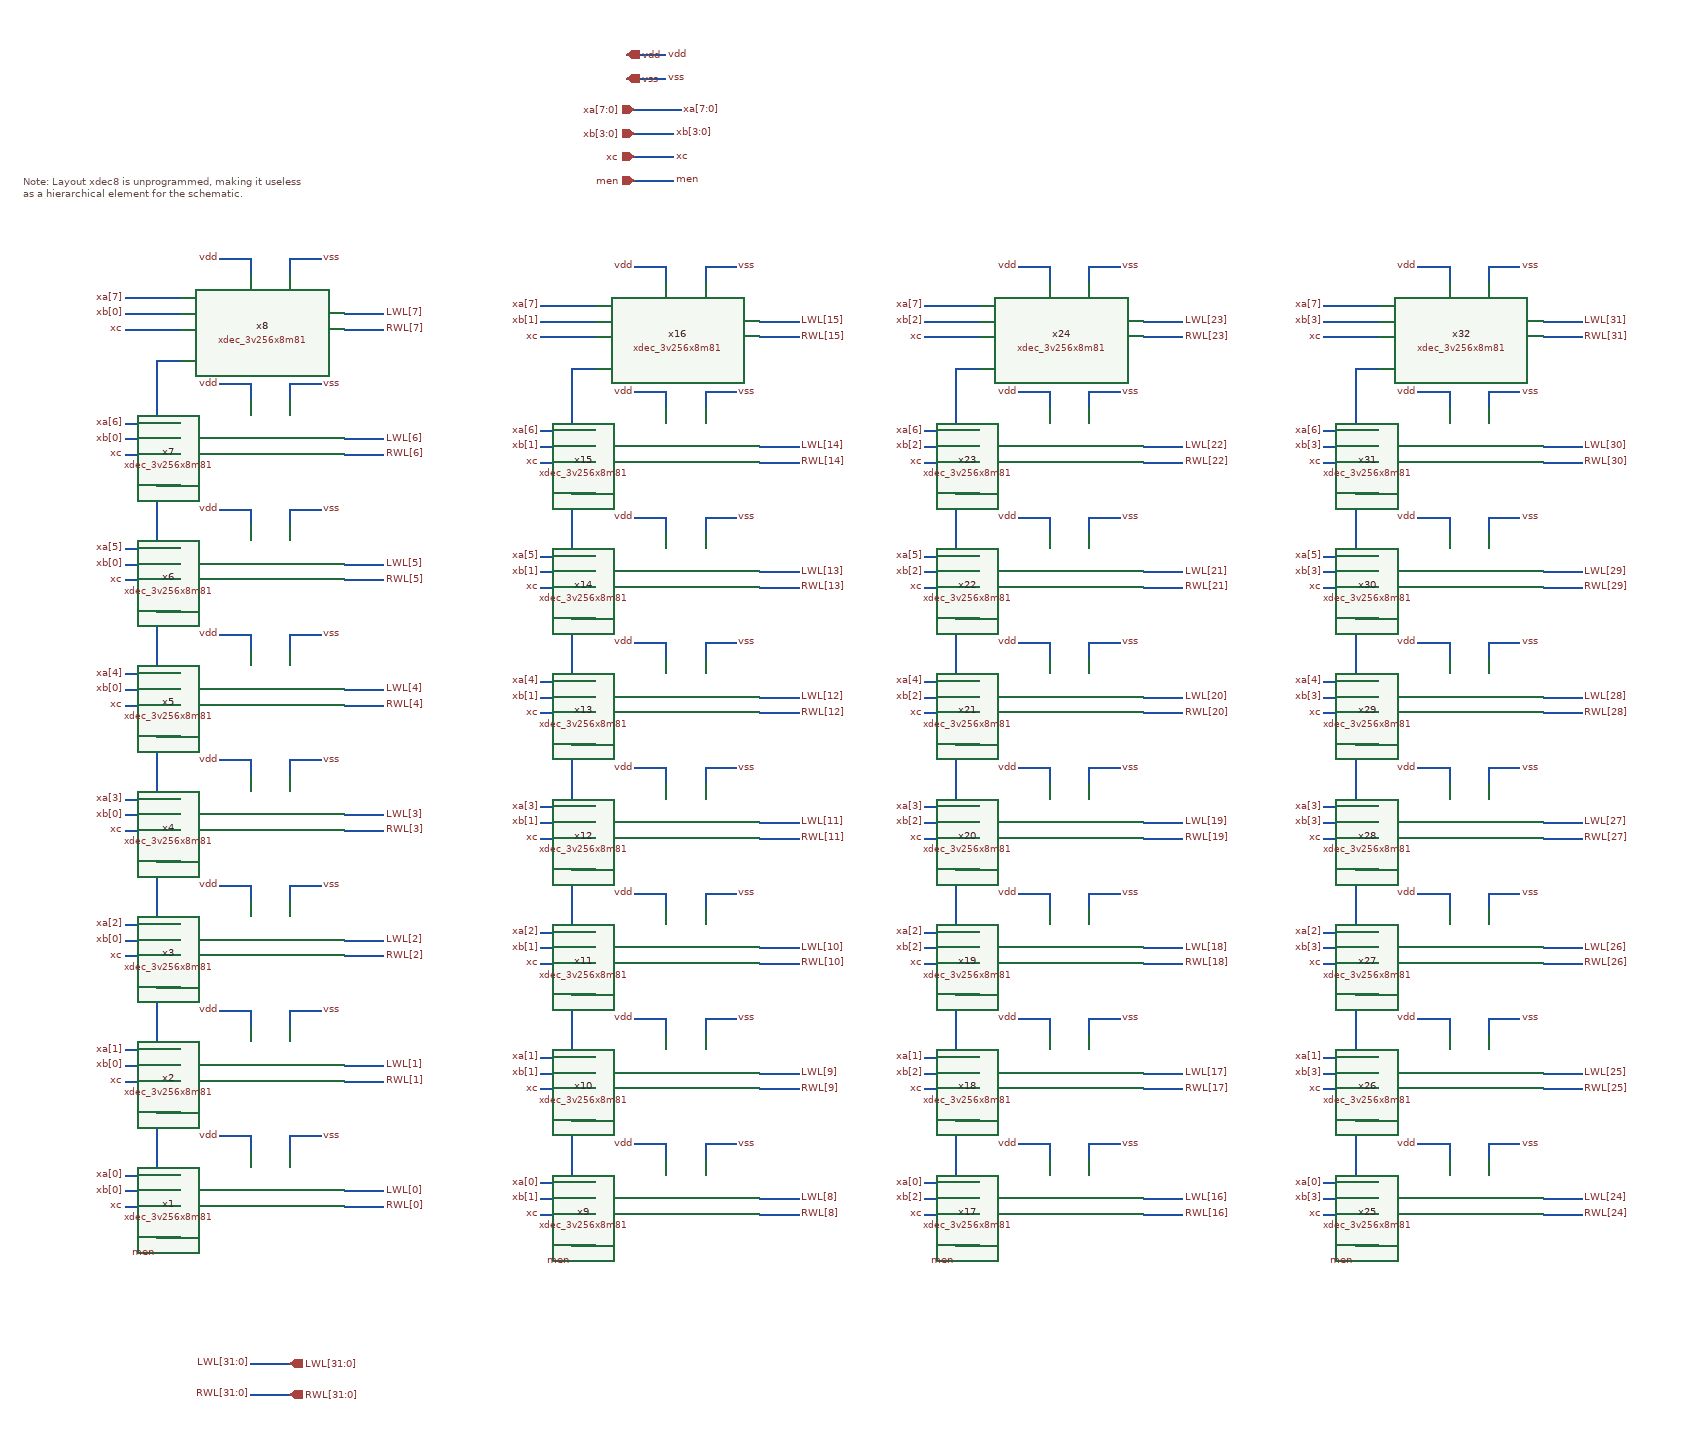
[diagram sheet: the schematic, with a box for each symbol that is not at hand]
v {xschem version=3.4.6 file_version=1.2}
G {}
K {}
V {}
S {}
E {}
T {Note:  Layout xdec8 is unprogrammed, making it useless
as a hierarchical element for the schematic.} -200 -1260 0 0 0.4 0.4 {}
N 50 -30 90 -30 {lab=vdd}
N 140 -30 180 -30 {lab=vdd}
N 90 -30 90 -10 {lab=vdd}
N 140 -30 140 -10 {lab=vdd}
N 50 -190 90 -190 {lab=vdd}
N 140 -190 180 -190 {lab=vdd}
N 90 -190 90 -170 {lab=vdd}
N 140 -190 140 -170 {lab=vdd}
N 50 -350 90 -350 {lab=vdd}
N 140 -350 180 -350 {lab=vdd}
N 90 -350 90 -330 {lab=vdd}
N 140 -350 140 -330 {lab=vdd}
N 50 -510 90 -510 {lab=vdd}
N 140 -510 180 -510 {lab=vdd}
N 90 -510 90 -490 {lab=vdd}
N 140 -510 140 -490 {lab=vdd}
N 50 -670 90 -670 {lab=vdd}
N 140 -670 180 -670 {lab=vdd}
N 90 -670 90 -650 {lab=vdd}
N 140 -670 140 -650 {lab=vdd}
N 50 -830 90 -830 {lab=vdd}
N 140 -830 180 -830 {lab=vdd}
N 90 -830 90 -810 {lab=vdd}
N 140 -830 140 -810 {lab=vdd}
N 50 -990 90 -990 {lab=vdd}
N 140 -990 180 -990 {lab=vdd}
N 90 -990 90 -970 {lab=vdd}
N 140 -990 140 -970 {lab=vdd}
N 50 -1150 90 -1150 {lab=vdd}
N 140 -1150 180 -1150 {lab=vdd}
N 90 -1150 90 -1130 {lab=vdd}
N 140 -1150 140 -1130 {lab=vdd}
N 210 -1080 260 -1080 {lab=LWL[7]}
N 210 -1060 260 -1060 {lab=RWL[7]}
N -30 -1020 -0 -1020 {lab=men}
N 210 -920 260 -920 {lab=LWL[6]}
N 210 -900 260 -900 {lab=RWL[6]}
N -30 -860 0 -860 {lab=men}
N 210 -600 260 -600 {lab=LWL[4]}
N 210 -580 260 -580 {lab=RWL[4]}
N -30 -540 0 -540 {lab=men}
N 210 -760 260 -760 {lab=LWL[5]}
N 210 -740 260 -740 {lab=RWL[5]}
N -30 -700 0 -700 {lab=men}
N 210 -440 260 -440 {lab=LWL[3]}
N 210 -420 260 -420 {lab=RWL[3]}
N -30 -380 0 -380 {lab=men}
N 210 -280 260 -280 {lab=LWL[2]}
N 210 -260 260 -260 {lab=RWL[2]}
N -30 -220 0 -220 {lab=men}
N 210 40 260 40 {lab=LWL[0]}
N 210 60 260 60 {lab=RWL[0]}
N -30 100 0 100 {lab=men}
N 210 -120 260 -120 {lab=LWL[1]}
N 210 -100 260 -100 {lab=RWL[1]}
N -30 -60 0 -60 {lab=men}
N -30 -1020 -30 120 {lab=men}
N 580 -20 620 -20 {lab=vdd}
N 670 -20 710 -20 {lab=vdd}
N 620 -20 620 0 {lab=vdd}
N 670 -20 670 0 {lab=vdd}
N 580 -180 620 -180 {lab=vdd}
N 670 -180 710 -180 {lab=vdd}
N 620 -180 620 -160 {lab=vdd}
N 670 -180 670 -160 {lab=vdd}
N 580 -340 620 -340 {lab=vdd}
N 670 -340 710 -340 {lab=vdd}
N 620 -340 620 -320 {lab=vdd}
N 670 -340 670 -320 {lab=vdd}
N 580 -500 620 -500 {lab=vdd}
N 670 -500 710 -500 {lab=vdd}
N 620 -500 620 -480 {lab=vdd}
N 670 -500 670 -480 {lab=vdd}
N 580 -660 620 -660 {lab=vdd}
N 670 -660 710 -660 {lab=vdd}
N 620 -660 620 -640 {lab=vdd}
N 670 -660 670 -640 {lab=vdd}
N 580 -820 620 -820 {lab=vdd}
N 670 -820 710 -820 {lab=vdd}
N 620 -820 620 -800 {lab=vdd}
N 670 -820 670 -800 {lab=vdd}
N 580 -980 620 -980 {lab=vdd}
N 670 -980 710 -980 {lab=vdd}
N 620 -980 620 -960 {lab=vdd}
N 670 -980 670 -960 {lab=vdd}
N 580 -1140 620 -1140 {lab=vdd}
N 670 -1140 710 -1140 {lab=vdd}
N 620 -1140 620 -1120 {lab=vdd}
N 670 -1140 670 -1120 {lab=vdd}
N 740 -1070 790 -1070 {lab=LWL[15]}
N 740 -1050 790 -1050 {lab=RWL[15]}
N 500 -1010 530 -1010 {lab=men}
N 740 -910 790 -910 {lab=LWL[14]}
N 740 -890 790 -890 {lab=RWL[14]}
N 500 -850 530 -850 {lab=men}
N 740 -590 790 -590 {lab=LWL[12]}
N 740 -570 790 -570 {lab=RWL[12]}
N 500 -530 530 -530 {lab=men}
N 740 -750 790 -750 {lab=LWL[13]}
N 740 -730 790 -730 {lab=RWL[13]}
N 500 -690 530 -690 {lab=men}
N 740 -430 790 -430 {lab=LWL[11]}
N 740 -410 790 -410 {lab=RWL[11]}
N 500 -370 530 -370 {lab=men}
N 740 -270 790 -270 {lab=LWL[10]}
N 740 -250 790 -250 {lab=RWL[10]}
N 500 -210 530 -210 {lab=men}
N 740 50 790 50 {lab=LWL[8]}
N 740 70 790 70 {lab=RWL[8]}
N 500 110 530 110 {lab=men}
N 740 -110 790 -110 {lab=LWL[9]}
N 740 -90 790 -90 {lab=RWL[9]}
N 500 -50 530 -50 {lab=men}
N 500 -1010 500 130 {lab=men}
N 1070 -20 1110 -20 {lab=vdd}
N 1160 -20 1200 -20 {lab=vdd}
N 1110 -20 1110 0 {lab=vdd}
N 1160 -20 1160 0 {lab=vdd}
N 1070 -180 1110 -180 {lab=vdd}
N 1160 -180 1200 -180 {lab=vdd}
N 1110 -180 1110 -160 {lab=vdd}
N 1160 -180 1160 -160 {lab=vdd}
N 1070 -340 1110 -340 {lab=vdd}
N 1160 -340 1200 -340 {lab=vdd}
N 1110 -340 1110 -320 {lab=vdd}
N 1160 -340 1160 -320 {lab=vdd}
N 1070 -500 1110 -500 {lab=vdd}
N 1160 -500 1200 -500 {lab=vdd}
N 1110 -500 1110 -480 {lab=vdd}
N 1160 -500 1160 -480 {lab=vdd}
N 1070 -660 1110 -660 {lab=vdd}
N 1160 -660 1200 -660 {lab=vdd}
N 1110 -660 1110 -640 {lab=vdd}
N 1160 -660 1160 -640 {lab=vdd}
N 1070 -820 1110 -820 {lab=vdd}
N 1160 -820 1200 -820 {lab=vdd}
N 1110 -820 1110 -800 {lab=vdd}
N 1160 -820 1160 -800 {lab=vdd}
N 1070 -980 1110 -980 {lab=vdd}
N 1160 -980 1200 -980 {lab=vdd}
N 1110 -980 1110 -960 {lab=vdd}
N 1160 -980 1160 -960 {lab=vdd}
N 1070 -1140 1110 -1140 {lab=vdd}
N 1160 -1140 1200 -1140 {lab=vdd}
N 1110 -1140 1110 -1120 {lab=vdd}
N 1160 -1140 1160 -1120 {lab=vdd}
N 1230 -1070 1280 -1070 {lab=LWL[23]}
N 1230 -1050 1280 -1050 {lab=RWL[23]}
N 990 -1010 1020 -1010 {lab=men}
N 1230 -910 1280 -910 {lab=LWL[22]}
N 1230 -890 1280 -890 {lab=RWL[22]}
N 990 -850 1020 -850 {lab=men}
N 1230 -590 1280 -590 {lab=LWL[20]}
N 1230 -570 1280 -570 {lab=RWL[20]}
N 990 -530 1020 -530 {lab=men}
N 1230 -750 1280 -750 {lab=LWL[21]}
N 1230 -730 1280 -730 {lab=RWL[21]}
N 990 -690 1020 -690 {lab=men}
N 1230 -430 1280 -430 {lab=LWL[19]}
N 1230 -410 1280 -410 {lab=RWL[19]}
N 990 -370 1020 -370 {lab=men}
N 1230 -270 1280 -270 {lab=LWL[18]}
N 1230 -250 1280 -250 {lab=RWL[18]}
N 990 -210 1020 -210 {lab=men}
N 1230 50 1280 50 {lab=LWL[16]}
N 1230 70 1280 70 {lab=RWL[16]}
N 990 110 1020 110 {lab=men}
N 1230 -110 1280 -110 {lab=LWL[17]}
N 1230 -90 1280 -90 {lab=RWL[17]}
N 990 -50 1020 -50 {lab=men}
N 990 -1010 990 130 {lab=men}
N 1580 -20 1620 -20 {lab=vdd}
N 1670 -20 1710 -20 {lab=vdd}
N 1620 -20 1620 0 {lab=vdd}
N 1670 -20 1670 0 {lab=vdd}
N 1580 -180 1620 -180 {lab=vdd}
N 1670 -180 1710 -180 {lab=vdd}
N 1620 -180 1620 -160 {lab=vdd}
N 1670 -180 1670 -160 {lab=vdd}
N 1580 -340 1620 -340 {lab=vdd}
N 1670 -340 1710 -340 {lab=vdd}
N 1620 -340 1620 -320 {lab=vdd}
N 1670 -340 1670 -320 {lab=vdd}
N 1580 -500 1620 -500 {lab=vdd}
N 1670 -500 1710 -500 {lab=vdd}
N 1620 -500 1620 -480 {lab=vdd}
N 1670 -500 1670 -480 {lab=vdd}
N 1580 -660 1620 -660 {lab=vdd}
N 1670 -660 1710 -660 {lab=vdd}
N 1620 -660 1620 -640 {lab=vdd}
N 1670 -660 1670 -640 {lab=vdd}
N 1580 -820 1620 -820 {lab=vdd}
N 1670 -820 1710 -820 {lab=vdd}
N 1620 -820 1620 -800 {lab=vdd}
N 1670 -820 1670 -800 {lab=vdd}
N 1580 -980 1620 -980 {lab=vdd}
N 1670 -980 1710 -980 {lab=vdd}
N 1620 -980 1620 -960 {lab=vdd}
N 1670 -980 1670 -960 {lab=vdd}
N 1580 -1140 1620 -1140 {lab=vdd}
N 1670 -1140 1710 -1140 {lab=vdd}
N 1620 -1140 1620 -1120 {lab=vdd}
N 1670 -1140 1670 -1120 {lab=vdd}
N 1740 -1070 1790 -1070 {lab=LWL[31]}
N 1740 -1050 1790 -1050 {lab=RWL[31]}
N 1500 -1010 1530 -1010 {lab=men}
N 1740 -910 1790 -910 {lab=LWL[30]}
N 1740 -890 1790 -890 {lab=RWL[30]}
N 1500 -850 1530 -850 {lab=men}
N 1740 -590 1790 -590 {lab=LWL[28]}
N 1740 -570 1790 -570 {lab=RWL[28]}
N 1500 -530 1530 -530 {lab=men}
N 1740 -750 1790 -750 {lab=LWL[29]}
N 1740 -730 1790 -730 {lab=RWL[29]}
N 1500 -690 1530 -690 {lab=men}
N 1740 -430 1790 -430 {lab=LWL[27]}
N 1740 -410 1790 -410 {lab=RWL[27]}
N 1500 -370 1530 -370 {lab=men}
N 1740 -270 1790 -270 {lab=LWL[26]}
N 1740 -250 1790 -250 {lab=RWL[26]}
N 1500 -210 1530 -210 {lab=men}
N 1740 50 1790 50 {lab=LWL[24]}
N 1740 70 1790 70 {lab=RWL[24]}
N 1500 110 1530 110 {lab=men}
N 1740 -110 1790 -110 {lab=LWL[25]}
N 1740 -90 1790 -90 {lab=RWL[25]}
N 1500 -50 1530 -50 {lab=men}
N 1500 -1010 1500 130 {lab=men}
N 580 -1340 640 -1340 {lab=xa[7:0]}
N 580 -1310 630 -1310 {lab=xb[3:0]}
N 580 -1280 630 -1280 {lab=xc}
N 570 -1410 620 -1410 {lab=vdd}
N 570 -1380 620 -1380 {lab=vss}
N 90 260 140 260 {lab=LWL[31:0]}
N 90 300 140 300 {lab=RWL[31:0]}
N 580 -1250 630 -1250 {lab=men}
N -70 20 -0 20 {lab=xa[0]}
N -70 -140 0 -140 {lab=xa[1]}
N -70 -300 0 -300 {lab=xa[2]}
N -70 -460 0 -460 {lab=xa[3]}
N -70 -620 0 -620 {lab=xa[4]}
N -70 -780 0 -780 {lab=xa[5]}
N -70 -940 0 -940 {lab=xa[6]}
N -70 -1100 0 -1100 {lab=xa[7]}
N 460 30 530 30 {lab=xa[0]}
N 460 -130 530 -130 {lab=xa[1]}
N 460 -290 530 -290 {lab=xa[2]}
N 460 -450 530 -450 {lab=xa[3]}
N 460 -610 530 -610 {lab=xa[4]}
N 460 -770 530 -770 {lab=xa[5]}
N 460 -930 530 -930 {lab=xa[6]}
N 460 -1090 530 -1090 {lab=xa[7]}
N 950 30 1020 30 {lab=xa[0]}
N 950 -130 1020 -130 {lab=xa[1]}
N 950 -290 1020 -290 {lab=xa[2]}
N 950 -450 1020 -450 {lab=xa[3]}
N 950 -610 1020 -610 {lab=xa[4]}
N 950 -770 1020 -770 {lab=xa[5]}
N 950 -930 1020 -930 {lab=xa[6]}
N 950 -1090 1020 -1090 {lab=xa[7]}
N 1460 30 1530 30 {lab=xa[0]}
N 1460 -130 1530 -130 {lab=xa[1]}
N 1460 -290 1530 -290 {lab=xa[2]}
N 1460 -450 1530 -450 {lab=xa[3]}
N 1460 -610 1530 -610 {lab=xa[4]}
N 1460 -770 1530 -770 {lab=xa[5]}
N 1460 -930 1530 -930 {lab=xa[6]}
N 1460 -1090 1530 -1090 {lab=xa[7]}
N -70 60 -0 60 {lab=#net1}
N -70 40 -0 40 {lab=#net2}
N -70 -100 0 -100 {lab=#net1}
N -70 -120 0 -120 {lab=#net2}
N -70 -260 0 -260 {lab=#net1}
N -70 -280 0 -280 {lab=#net2}
N -70 -420 0 -420 {lab=#net1}
N -70 -440 0 -440 {lab=#net2}
N -70 -580 0 -580 {lab=#net1}
N -70 -600 0 -600 {lab=#net2}
N -70 -740 0 -740 {lab=#net1}
N -70 -760 0 -760 {lab=#net2}
N -70 -900 0 -900 {lab=#net1}
N -70 -920 0 -920 {lab=#net2}
N -70 -1060 0 -1060 {lab=#net1}
N -70 -1080 0 -1080 {lab=#net2}
N 460 70 530 70 {lab=#net1}
N 460 50 530 50 {lab=#net2}
N 460 -90 530 -90 {lab=#net1}
N 460 -110 530 -110 {lab=#net2}
N 460 -250 530 -250 {lab=#net1}
N 460 -270 530 -270 {lab=#net2}
N 460 -410 530 -410 {lab=#net1}
N 460 -430 530 -430 {lab=#net2}
N 460 -570 530 -570 {lab=#net1}
N 460 -590 530 -590 {lab=#net2}
N 460 -730 530 -730 {lab=#net1}
N 460 -750 530 -750 {lab=#net2}
N 460 -890 530 -890 {lab=#net1}
N 460 -910 530 -910 {lab=#net2}
N 460 -1050 530 -1050 {lab=#net1}
N 460 -1070 530 -1070 {lab=#net2}
N 950 70 1020 70 {lab=#net1}
N 950 50 1020 50 {lab=#net2}
N 950 -90 1020 -90 {lab=#net1}
N 950 -110 1020 -110 {lab=#net2}
N 950 -250 1020 -250 {lab=#net1}
N 950 -270 1020 -270 {lab=#net2}
N 950 -410 1020 -410 {lab=#net1}
N 950 -430 1020 -430 {lab=#net2}
N 950 -570 1020 -570 {lab=#net1}
N 950 -590 1020 -590 {lab=#net2}
N 950 -730 1020 -730 {lab=#net1}
N 950 -750 1020 -750 {lab=#net2}
N 950 -890 1020 -890 {lab=#net1}
N 950 -910 1020 -910 {lab=#net2}
N 950 -1050 1020 -1050 {lab=#net1}
N 950 -1070 1020 -1070 {lab=#net2}
N 1460 70 1530 70 {lab=#net1}
N 1460 50 1530 50 {lab=#net2}
N 1460 -90 1530 -90 {lab=#net1}
N 1460 -110 1530 -110 {lab=#net2}
N 1460 -250 1530 -250 {lab=#net1}
N 1460 -270 1530 -270 {lab=#net2}
N 1460 -410 1530 -410 {lab=#net1}
N 1460 -430 1530 -430 {lab=#net2}
N 1460 -570 1530 -570 {lab=#net1}
N 1460 -590 1530 -590 {lab=#net2}
N 1460 -730 1530 -730 {lab=#net1}
N 1460 -750 1530 -750 {lab=#net2}
N 1460 -890 1530 -890 {lab=#net1}
N 1460 -910 1530 -910 {lab=#net2}
N 1460 -1050 1530 -1050 {lab=#net1}
N 1460 -1070 1530 -1070 {lab=#net2}
C {xdec_3v256x8m81.sym} 150 50 0 0 {name=x1}
C {xdec_3v256x8m81.sym} 150 -110 0 0 {name=x2}
C {xdec_3v256x8m81.sym} 150 -270 0 0 {name=x3}
C {xdec_3v256x8m81.sym} 150 -430 0 0 {name=x4}
C {xdec_3v256x8m81.sym} 150 -590 0 0 {name=x5}
C {xdec_3v256x8m81.sym} 150 -750 0 0 {name=x6}
C {xdec_3v256x8m81.sym} 150 -910 0 0 {name=x7}
C {xdec_3v256x8m81.sym} 150 -1070 0 0 {name=x8}
C {lab_pin.sym} 50 -30 0 0 {name=p1 sig_type=std_logic lab=vdd}
C {lab_pin.sym} 50 -190 0 0 {name=p3 sig_type=std_logic lab=vdd}
C {lab_pin.sym} 50 -350 0 0 {name=p5 sig_type=std_logic lab=vdd}
C {lab_pin.sym} 50 -510 0 0 {name=p7 sig_type=std_logic lab=vdd}
C {lab_pin.sym} 50 -670 0 0 {name=p9 sig_type=std_logic lab=vdd}
C {lab_pin.sym} 50 -830 0 0 {name=p11 sig_type=std_logic lab=vdd}
C {lab_pin.sym} 50 -990 0 0 {name=p13 sig_type=std_logic lab=vdd}
C {lab_pin.sym} 50 -1150 0 0 {name=p15 sig_type=std_logic lab=vdd}
C {xdec_3v256x8m81.sym} 680 60 0 0 {name=x9}
C {xdec_3v256x8m81.sym} 680 -100 0 0 {name=x10}
C {xdec_3v256x8m81.sym} 680 -260 0 0 {name=x11}
C {xdec_3v256x8m81.sym} 680 -420 0 0 {name=x12}
C {xdec_3v256x8m81.sym} 680 -580 0 0 {name=x13}
C {xdec_3v256x8m81.sym} 680 -740 0 0 {name=x14}
C {xdec_3v256x8m81.sym} 680 -900 0 0 {name=x15}
C {xdec_3v256x8m81.sym} 680 -1060 0 0 {name=x16}
C {lab_pin.sym} 580 -20 0 0 {name=p17 sig_type=std_logic lab=vdd}
C {lab_pin.sym} 580 -180 0 0 {name=p19 sig_type=std_logic lab=vdd}
C {lab_pin.sym} 580 -340 0 0 {name=p21 sig_type=std_logic lab=vdd}
C {lab_pin.sym} 580 -500 0 0 {name=p23 sig_type=std_logic lab=vdd}
C {lab_pin.sym} 580 -660 0 0 {name=p25 sig_type=std_logic lab=vdd}
C {lab_pin.sym} 580 -820 0 0 {name=p27 sig_type=std_logic lab=vdd}
C {lab_pin.sym} 580 -980 0 0 {name=p29 sig_type=std_logic lab=vdd}
C {lab_pin.sym} 580 -1140 0 0 {name=p31 sig_type=std_logic lab=vdd}
C {xdec_3v256x8m81.sym} 1170 60 0 0 {name=x17}
C {xdec_3v256x8m81.sym} 1170 -100 0 0 {name=x18}
C {xdec_3v256x8m81.sym} 1170 -260 0 0 {name=x19}
C {xdec_3v256x8m81.sym} 1170 -420 0 0 {name=x20}
C {xdec_3v256x8m81.sym} 1170 -580 0 0 {name=x21}
C {xdec_3v256x8m81.sym} 1170 -740 0 0 {name=x22}
C {xdec_3v256x8m81.sym} 1170 -900 0 0 {name=x23}
C {xdec_3v256x8m81.sym} 1170 -1060 0 0 {name=x24}
C {lab_pin.sym} 1070 -20 0 0 {name=p33 sig_type=std_logic lab=vdd}
C {lab_pin.sym} 1070 -180 0 0 {name=p35 sig_type=std_logic lab=vdd}
C {lab_pin.sym} 1070 -340 0 0 {name=p37 sig_type=std_logic lab=vdd}
C {lab_pin.sym} 1070 -500 0 0 {name=p39 sig_type=std_logic lab=vdd}
C {lab_pin.sym} 1070 -660 0 0 {name=p41 sig_type=std_logic lab=vdd}
C {lab_pin.sym} 1070 -820 0 0 {name=p43 sig_type=std_logic lab=vdd}
C {lab_pin.sym} 1070 -980 0 0 {name=p45 sig_type=std_logic lab=vdd}
C {lab_pin.sym} 1070 -1140 0 0 {name=p47 sig_type=std_logic lab=vdd}
C {xdec_3v256x8m81.sym} 1680 60 0 0 {name=x25}
C {xdec_3v256x8m81.sym} 1680 -100 0 0 {name=x26}
C {xdec_3v256x8m81.sym} 1680 -260 0 0 {name=x27}
C {xdec_3v256x8m81.sym} 1680 -420 0 0 {name=x28}
C {xdec_3v256x8m81.sym} 1680 -580 0 0 {name=x29}
C {xdec_3v256x8m81.sym} 1680 -740 0 0 {name=x30}
C {xdec_3v256x8m81.sym} 1680 -900 0 0 {name=x31}
C {xdec_3v256x8m81.sym} 1680 -1060 0 0 {name=x32}
C {lab_pin.sym} 1580 -20 0 0 {name=p49 sig_type=std_logic lab=vdd}
C {lab_pin.sym} 1580 -180 0 0 {name=p51 sig_type=std_logic lab=vdd}
C {lab_pin.sym} 1580 -340 0 0 {name=p53 sig_type=std_logic lab=vdd}
C {lab_pin.sym} 1580 -500 0 0 {name=p55 sig_type=std_logic lab=vdd}
C {lab_pin.sym} 1580 -660 0 0 {name=p57 sig_type=std_logic lab=vdd}
C {lab_pin.sym} 1580 -820 0 0 {name=p59 sig_type=std_logic lab=vdd}
C {lab_pin.sym} 1580 -980 0 0 {name=p61 sig_type=std_logic lab=vdd}
C {lab_pin.sym} 1580 -1140 0 0 {name=p63 sig_type=std_logic lab=vdd}
C {ipin.sym} 580 -1340 0 0 {name=p65 lab=xa[7:0]}
C {lab_pin.sym} 640 -1340 0 1 {name=p66 sig_type=std_logic lab=xa[7:0]}
C {ipin.sym} 580 -1310 0 0 {name=p67 lab=xb[3:0]}
C {lab_pin.sym} 630 -1310 0 1 {name=p68 sig_type=std_logic lab=xb[3:0]}
C {ipin.sym} 580 -1280 0 0 {name=p69 lab=xc}
C {lab_pin.sym} 630 -1280 0 1 {name=p70 sig_type=std_logic lab=xc}
C {iopin.sym} 570 -1410 0 1 {name=p71 lab=vdd}
C {lab_pin.sym} 620 -1410 0 1 {name=p72 sig_type=std_logic lab=vdd}
C {iopin.sym} 570 -1380 0 1 {name=p73 lab=vss}
C {lab_pin.sym} 620 -1380 0 1 {name=p74 sig_type=std_logic lab=vss}
C {opin.sym} 140 300 0 0 {name=p75 lab=RWL[31:0]}
C {opin.sym} 140 260 0 0 {name=p76 lab=LWL[31:0]}
C {lab_pin.sym} 90 260 0 0 {name=p77 sig_type=std_logic lab=LWL[31:0]}
C {lab_pin.sym} 90 300 0 0 {name=p78 sig_type=std_logic lab=RWL[31:0]}
C {lab_pin.sym} 260 40 0 1 {name=p79 sig_type=std_logic lab=LWL[0]}
C {lab_pin.sym} 260 60 0 1 {name=p80 sig_type=std_logic lab=RWL[0]}
C {lab_pin.sym} 260 -120 0 1 {name=p81 sig_type=std_logic lab=LWL[1]}
C {lab_pin.sym} 260 -100 0 1 {name=p82 sig_type=std_logic lab=RWL[1]}
C {lab_pin.sym} 260 -280 0 1 {name=p83 sig_type=std_logic lab=LWL[2]}
C {lab_pin.sym} 260 -260 0 1 {name=p84 sig_type=std_logic lab=RWL[2]}
C {lab_pin.sym} 260 -440 0 1 {name=p85 sig_type=std_logic lab=LWL[3]}
C {lab_pin.sym} 260 -420 0 1 {name=p86 sig_type=std_logic lab=RWL[3]}
C {lab_pin.sym} 260 -600 0 1 {name=p87 sig_type=std_logic lab=LWL[4]}
C {lab_pin.sym} 260 -580 0 1 {name=p88 sig_type=std_logic lab=RWL[4]}
C {lab_pin.sym} 260 -760 0 1 {name=p89 sig_type=std_logic lab=LWL[5]}
C {lab_pin.sym} 260 -740 0 1 {name=p90 sig_type=std_logic lab=RWL[5]}
C {lab_pin.sym} 260 -920 0 1 {name=p91 sig_type=std_logic lab=LWL[6]}
C {lab_pin.sym} 260 -900 0 1 {name=p92 sig_type=std_logic lab=RWL[6]}
C {lab_pin.sym} 260 -1080 0 1 {name=p93 sig_type=std_logic lab=LWL[7]}
C {lab_pin.sym} 260 -1060 0 1 {name=p94 sig_type=std_logic lab=RWL[7]}
C {lab_pin.sym} 790 50 0 1 {name=p95 sig_type=std_logic lab=LWL[8]}
C {lab_pin.sym} 790 70 0 1 {name=p96 sig_type=std_logic lab=RWL[8]}
C {lab_pin.sym} 790 -110 0 1 {name=p97 sig_type=std_logic lab=LWL[9]}
C {lab_pin.sym} 790 -90 0 1 {name=p98 sig_type=std_logic lab=RWL[9]}
C {lab_pin.sym} 790 -270 0 1 {name=p99 sig_type=std_logic lab=LWL[10]}
C {lab_pin.sym} 790 -250 0 1 {name=p100 sig_type=std_logic lab=RWL[10]}
C {lab_pin.sym} 790 -430 0 1 {name=p101 sig_type=std_logic lab=LWL[11]}
C {lab_pin.sym} 790 -410 0 1 {name=p102 sig_type=std_logic lab=RWL[11]}
C {lab_pin.sym} 790 -590 0 1 {name=p103 sig_type=std_logic lab=LWL[12]}
C {lab_pin.sym} 790 -570 0 1 {name=p104 sig_type=std_logic lab=RWL[12]}
C {lab_pin.sym} 790 -750 0 1 {name=p105 sig_type=std_logic lab=LWL[13]}
C {lab_pin.sym} 790 -730 0 1 {name=p106 sig_type=std_logic lab=RWL[13]}
C {lab_pin.sym} 790 -910 0 1 {name=p107 sig_type=std_logic lab=LWL[14]}
C {lab_pin.sym} 790 -890 0 1 {name=p108 sig_type=std_logic lab=RWL[14]}
C {lab_pin.sym} 790 -1070 0 1 {name=p109 sig_type=std_logic lab=LWL[15]}
C {lab_pin.sym} 790 -1050 0 1 {name=p110 sig_type=std_logic lab=RWL[15]}
C {lab_pin.sym} 1280 50 0 1 {name=p111 sig_type=std_logic lab=LWL[16]}
C {lab_pin.sym} 1280 70 0 1 {name=p112 sig_type=std_logic lab=RWL[16]}
C {lab_pin.sym} 1280 -110 0 1 {name=p113 sig_type=std_logic lab=LWL[17]}
C {lab_pin.sym} 1280 -90 0 1 {name=p114 sig_type=std_logic lab=RWL[17]}
C {lab_pin.sym} 1280 -270 0 1 {name=p115 sig_type=std_logic lab=LWL[18]}
C {lab_pin.sym} 1280 -250 0 1 {name=p116 sig_type=std_logic lab=RWL[18]}
C {lab_pin.sym} 1280 -430 0 1 {name=p117 sig_type=std_logic lab=LWL[19]}
C {lab_pin.sym} 1280 -410 0 1 {name=p118 sig_type=std_logic lab=RWL[19]}
C {lab_pin.sym} 1280 -590 0 1 {name=p119 sig_type=std_logic lab=LWL[20]}
C {lab_pin.sym} 1280 -570 0 1 {name=p120 sig_type=std_logic lab=RWL[20]}
C {lab_pin.sym} 1280 -750 0 1 {name=p121 sig_type=std_logic lab=LWL[21]}
C {lab_pin.sym} 1280 -730 0 1 {name=p122 sig_type=std_logic lab=RWL[21]}
C {lab_pin.sym} 1280 -910 0 1 {name=p123 sig_type=std_logic lab=LWL[22]}
C {lab_pin.sym} 1280 -890 0 1 {name=p124 sig_type=std_logic lab=RWL[22]}
C {lab_pin.sym} 1280 -1070 0 1 {name=p125 sig_type=std_logic lab=LWL[23]}
C {lab_pin.sym} 1280 -1050 0 1 {name=p126 sig_type=std_logic lab=RWL[23]}
C {lab_pin.sym} 1790 50 0 1 {name=p127 sig_type=std_logic lab=LWL[24]}
C {lab_pin.sym} 1790 70 0 1 {name=p128 sig_type=std_logic lab=RWL[24]}
C {lab_pin.sym} 1790 -110 0 1 {name=p129 sig_type=std_logic lab=LWL[25]}
C {lab_pin.sym} 1790 -90 0 1 {name=p130 sig_type=std_logic lab=RWL[25]}
C {lab_pin.sym} 1790 -270 0 1 {name=p131 sig_type=std_logic lab=LWL[26]}
C {lab_pin.sym} 1790 -250 0 1 {name=p132 sig_type=std_logic lab=RWL[26]}
C {lab_pin.sym} 1790 -430 0 1 {name=p133 sig_type=std_logic lab=LWL[27]}
C {lab_pin.sym} 1790 -410 0 1 {name=p134 sig_type=std_logic lab=RWL[27]}
C {lab_pin.sym} 1790 -590 0 1 {name=p135 sig_type=std_logic lab=LWL[28]}
C {lab_pin.sym} 1790 -570 0 1 {name=p136 sig_type=std_logic lab=RWL[28]}
C {lab_pin.sym} 1790 -750 0 1 {name=p137 sig_type=std_logic lab=LWL[29]}
C {lab_pin.sym} 1790 -730 0 1 {name=p138 sig_type=std_logic lab=RWL[29]}
C {lab_pin.sym} 1790 -910 0 1 {name=p139 sig_type=std_logic lab=LWL[30]}
C {lab_pin.sym} 1790 -890 0 1 {name=p140 sig_type=std_logic lab=RWL[30]}
C {lab_pin.sym} 1790 -1070 0 1 {name=p141 sig_type=std_logic lab=LWL[31]}
C {lab_pin.sym} 1790 -1050 0 1 {name=p142 sig_type=std_logic lab=RWL[31]}
C {ipin.sym} 580 -1250 0 0 {name=p143 lab=men}
C {lab_pin.sym} 630 -1250 0 1 {name=p144 sig_type=std_logic lab=men}
C {lab_pin.sym} -30 120 1 1 {name=p145 sig_type=std_logic lab=men}
C {lab_pin.sym} 500 130 1 1 {name=p146 sig_type=std_logic lab=men}
C {lab_pin.sym} 990 130 1 1 {name=p147 sig_type=std_logic lab=men}
C {lab_pin.sym} 1500 130 1 1 {name=p148 sig_type=std_logic lab=men}
C {lab_pin.sym} -70 20 0 0 {name=p149 sig_type=std_logic lab=xa[0]}
C {lab_pin.sym} -70 -140 0 0 {name=p150 sig_type=std_logic lab=xa[1]}
C {lab_pin.sym} -70 -300 0 0 {name=p151 sig_type=std_logic lab=xa[2]}
C {lab_pin.sym} -70 -460 0 0 {name=p152 sig_type=std_logic lab=xa[3]}
C {lab_pin.sym} -70 -620 0 0 {name=p153 sig_type=std_logic lab=xa[4]}
C {lab_pin.sym} -70 -780 0 0 {name=p154 sig_type=std_logic lab=xa[5]}
C {lab_pin.sym} -70 -940 0 0 {name=p155 sig_type=std_logic lab=xa[6]}
C {lab_pin.sym} -70 -1100 0 0 {name=p156 sig_type=std_logic lab=xa[7]}
C {lab_pin.sym} 460 30 0 0 {name=p157 sig_type=std_logic lab=xa[0]}
C {lab_pin.sym} 460 -130 0 0 {name=p158 sig_type=std_logic lab=xa[1]}
C {lab_pin.sym} 460 -290 0 0 {name=p159 sig_type=std_logic lab=xa[2]}
C {lab_pin.sym} 460 -450 0 0 {name=p160 sig_type=std_logic lab=xa[3]}
C {lab_pin.sym} 460 -610 0 0 {name=p161 sig_type=std_logic lab=xa[4]}
C {lab_pin.sym} 460 -770 0 0 {name=p162 sig_type=std_logic lab=xa[5]}
C {lab_pin.sym} 460 -930 0 0 {name=p163 sig_type=std_logic lab=xa[6]}
C {lab_pin.sym} 460 -1090 0 0 {name=p164 sig_type=std_logic lab=xa[7]}
C {lab_pin.sym} 950 30 0 0 {name=p165 sig_type=std_logic lab=xa[0]}
C {lab_pin.sym} 950 -130 0 0 {name=p166 sig_type=std_logic lab=xa[1]}
C {lab_pin.sym} 950 -290 0 0 {name=p167 sig_type=std_logic lab=xa[2]}
C {lab_pin.sym} 950 -450 0 0 {name=p168 sig_type=std_logic lab=xa[3]}
C {lab_pin.sym} 950 -610 0 0 {name=p169 sig_type=std_logic lab=xa[4]}
C {lab_pin.sym} 950 -770 0 0 {name=p170 sig_type=std_logic lab=xa[5]}
C {lab_pin.sym} 950 -930 0 0 {name=p171 sig_type=std_logic lab=xa[6]}
C {lab_pin.sym} 950 -1090 0 0 {name=p172 sig_type=std_logic lab=xa[7]}
C {lab_pin.sym} 1460 30 0 0 {name=p173 sig_type=std_logic lab=xa[0]}
C {lab_pin.sym} 1460 -130 0 0 {name=p174 sig_type=std_logic lab=xa[1]}
C {lab_pin.sym} 1460 -290 0 0 {name=p175 sig_type=std_logic lab=xa[2]}
C {lab_pin.sym} 1460 -450 0 0 {name=p176 sig_type=std_logic lab=xa[3]}
C {lab_pin.sym} 1460 -610 0 0 {name=p177 sig_type=std_logic lab=xa[4]}
C {lab_pin.sym} 1460 -770 0 0 {name=p178 sig_type=std_logic lab=xa[5]}
C {lab_pin.sym} 1460 -930 0 0 {name=p179 sig_type=std_logic lab=xa[6]}
C {lab_pin.sym} 1460 -1090 0 0 {name=p180 sig_type=std_logic lab=xa[7]}
C {lab_pin.sym} -70 40 0 0 {name=p181 sig_type=std_logic lab=xb[0]}
C {lab_pin.sym} -70 60 0 0 {name=p182 sig_type=std_logic lab=xc}
C {lab_pin.sym} -70 -120 0 0 {name=p183 sig_type=std_logic lab=xb[0]}
C {lab_pin.sym} -70 -100 0 0 {name=p184 sig_type=std_logic lab=xc}
C {lab_pin.sym} -70 -280 0 0 {name=p185 sig_type=std_logic lab=xb[0]}
C {lab_pin.sym} -70 -260 0 0 {name=p186 sig_type=std_logic lab=xc}
C {lab_pin.sym} -70 -440 0 0 {name=p187 sig_type=std_logic lab=xb[0]}
C {lab_pin.sym} -70 -420 0 0 {name=p188 sig_type=std_logic lab=xc}
C {lab_pin.sym} -70 -600 0 0 {name=p189 sig_type=std_logic lab=xb[0]}
C {lab_pin.sym} -70 -580 0 0 {name=p190 sig_type=std_logic lab=xc}
C {lab_pin.sym} -70 -760 0 0 {name=p191 sig_type=std_logic lab=xb[0]}
C {lab_pin.sym} -70 -740 0 0 {name=p192 sig_type=std_logic lab=xc}
C {lab_pin.sym} -70 -920 0 0 {name=p193 sig_type=std_logic lab=xb[0]}
C {lab_pin.sym} -70 -900 0 0 {name=p194 sig_type=std_logic lab=xc}
C {lab_pin.sym} -70 -1080 0 0 {name=p195 sig_type=std_logic lab=xb[0]}
C {lab_pin.sym} -70 -1060 0 0 {name=p196 sig_type=std_logic lab=xc}
C {lab_pin.sym} 460 50 0 0 {name=p197 sig_type=std_logic lab=xb[1]}
C {lab_pin.sym} 460 70 0 0 {name=p198 sig_type=std_logic lab=xc}
C {lab_pin.sym} 460 -110 0 0 {name=p199 sig_type=std_logic lab=xb[1]}
C {lab_pin.sym} 460 -90 0 0 {name=p200 sig_type=std_logic lab=xc}
C {lab_pin.sym} 460 -270 0 0 {name=p201 sig_type=std_logic lab=xb[1]}
C {lab_pin.sym} 460 -250 0 0 {name=p202 sig_type=std_logic lab=xc}
C {lab_pin.sym} 460 -430 0 0 {name=p203 sig_type=std_logic lab=xb[1]}
C {lab_pin.sym} 460 -410 0 0 {name=p204 sig_type=std_logic lab=xc}
C {lab_pin.sym} 460 -590 0 0 {name=p205 sig_type=std_logic lab=xb[1]}
C {lab_pin.sym} 460 -570 0 0 {name=p206 sig_type=std_logic lab=xc}
C {lab_pin.sym} 460 -750 0 0 {name=p207 sig_type=std_logic lab=xb[1]}
C {lab_pin.sym} 460 -730 0 0 {name=p208 sig_type=std_logic lab=xc}
C {lab_pin.sym} 460 -910 0 0 {name=p209 sig_type=std_logic lab=xb[1]}
C {lab_pin.sym} 460 -890 0 0 {name=p210 sig_type=std_logic lab=xc}
C {lab_pin.sym} 460 -1070 0 0 {name=p211 sig_type=std_logic lab=xb[1]}
C {lab_pin.sym} 460 -1050 0 0 {name=p212 sig_type=std_logic lab=xc}
C {lab_pin.sym} 950 50 0 0 {name=p213 sig_type=std_logic lab=xb[2]}
C {lab_pin.sym} 950 70 0 0 {name=p214 sig_type=std_logic lab=xc}
C {lab_pin.sym} 950 -110 0 0 {name=p215 sig_type=std_logic lab=xb[2]}
C {lab_pin.sym} 950 -90 0 0 {name=p216 sig_type=std_logic lab=xc}
C {lab_pin.sym} 950 -270 0 0 {name=p217 sig_type=std_logic lab=xb[2]}
C {lab_pin.sym} 950 -250 0 0 {name=p218 sig_type=std_logic lab=xc}
C {lab_pin.sym} 950 -430 0 0 {name=p219 sig_type=std_logic lab=xb[2]}
C {lab_pin.sym} 950 -410 0 0 {name=p220 sig_type=std_logic lab=xc}
C {lab_pin.sym} 950 -590 0 0 {name=p221 sig_type=std_logic lab=xb[2]}
C {lab_pin.sym} 950 -570 0 0 {name=p222 sig_type=std_logic lab=xc}
C {lab_pin.sym} 950 -750 0 0 {name=p223 sig_type=std_logic lab=xb[2]}
C {lab_pin.sym} 950 -730 0 0 {name=p224 sig_type=std_logic lab=xc}
C {lab_pin.sym} 950 -910 0 0 {name=p225 sig_type=std_logic lab=xb[2]}
C {lab_pin.sym} 950 -890 0 0 {name=p226 sig_type=std_logic lab=xc}
C {lab_pin.sym} 950 -1070 0 0 {name=p227 sig_type=std_logic lab=xb[2]}
C {lab_pin.sym} 950 -1050 0 0 {name=p228 sig_type=std_logic lab=xc}
C {lab_pin.sym} 1460 50 0 0 {name=p229 sig_type=std_logic lab=xb[3]}
C {lab_pin.sym} 1460 70 0 0 {name=p230 sig_type=std_logic lab=xc}
C {lab_pin.sym} 1460 -110 0 0 {name=p231 sig_type=std_logic lab=xb[3]}
C {lab_pin.sym} 1460 -90 0 0 {name=p232 sig_type=std_logic lab=xc}
C {lab_pin.sym} 1460 -270 0 0 {name=p233 sig_type=std_logic lab=xb[3]}
C {lab_pin.sym} 1460 -250 0 0 {name=p234 sig_type=std_logic lab=xc}
C {lab_pin.sym} 1460 -430 0 0 {name=p235 sig_type=std_logic lab=xb[3]}
C {lab_pin.sym} 1460 -410 0 0 {name=p236 sig_type=std_logic lab=xc}
C {lab_pin.sym} 1460 -590 0 0 {name=p237 sig_type=std_logic lab=xb[3]}
C {lab_pin.sym} 1460 -570 0 0 {name=p238 sig_type=std_logic lab=xc}
C {lab_pin.sym} 1460 -750 0 0 {name=p239 sig_type=std_logic lab=xb[3]}
C {lab_pin.sym} 1460 -730 0 0 {name=p240 sig_type=std_logic lab=xc}
C {lab_pin.sym} 1460 -910 0 0 {name=p241 sig_type=std_logic lab=xb[3]}
C {lab_pin.sym} 1460 -890 0 0 {name=p242 sig_type=std_logic lab=xc}
C {lab_pin.sym} 1460 -1070 0 0 {name=p243 sig_type=std_logic lab=xb[3]}
C {lab_pin.sym} 1460 -1050 0 0 {name=p244 sig_type=std_logic lab=xc}
C {lab_pin.sym} 180 -1150 0 1 {name=p2 sig_type=std_logic lab=vss}
C {lab_pin.sym} 180 -990 0 1 {name=p4 sig_type=std_logic lab=vss}
C {lab_pin.sym} 180 -830 0 1 {name=p6 sig_type=std_logic lab=vss}
C {lab_pin.sym} 180 -670 0 1 {name=p8 sig_type=std_logic lab=vss}
C {lab_pin.sym} 180 -510 0 1 {name=p10 sig_type=std_logic lab=vss}
C {lab_pin.sym} 180 -350 0 1 {name=p12 sig_type=std_logic lab=vss}
C {lab_pin.sym} 180 -190 0 1 {name=p14 sig_type=std_logic lab=vss}
C {lab_pin.sym} 180 -30 0 1 {name=p16 sig_type=std_logic lab=vss}
C {lab_pin.sym} 710 -1140 0 1 {name=p18 sig_type=std_logic lab=vss}
C {lab_pin.sym} 710 -980 0 1 {name=p20 sig_type=std_logic lab=vss}
C {lab_pin.sym} 710 -820 0 1 {name=p22 sig_type=std_logic lab=vss}
C {lab_pin.sym} 710 -660 0 1 {name=p24 sig_type=std_logic lab=vss}
C {lab_pin.sym} 710 -500 0 1 {name=p26 sig_type=std_logic lab=vss}
C {lab_pin.sym} 710 -340 0 1 {name=p28 sig_type=std_logic lab=vss}
C {lab_pin.sym} 710 -180 0 1 {name=p30 sig_type=std_logic lab=vss}
C {lab_pin.sym} 710 -20 0 1 {name=p32 sig_type=std_logic lab=vss}
C {lab_pin.sym} 1200 -1140 0 1 {name=p34 sig_type=std_logic lab=vss}
C {lab_pin.sym} 1200 -980 0 1 {name=p36 sig_type=std_logic lab=vss}
C {lab_pin.sym} 1200 -820 0 1 {name=p38 sig_type=std_logic lab=vss}
C {lab_pin.sym} 1200 -660 0 1 {name=p40 sig_type=std_logic lab=vss}
C {lab_pin.sym} 1200 -500 0 1 {name=p42 sig_type=std_logic lab=vss}
C {lab_pin.sym} 1200 -340 0 1 {name=p44 sig_type=std_logic lab=vss}
C {lab_pin.sym} 1200 -180 0 1 {name=p46 sig_type=std_logic lab=vss}
C {lab_pin.sym} 1200 -20 0 1 {name=p48 sig_type=std_logic lab=vss}
C {lab_pin.sym} 1710 -1140 0 1 {name=p50 sig_type=std_logic lab=vss}
C {lab_pin.sym} 1710 -980 0 1 {name=p52 sig_type=std_logic lab=vss}
C {lab_pin.sym} 1710 -820 0 1 {name=p54 sig_type=std_logic lab=vss}
C {lab_pin.sym} 1710 -660 0 1 {name=p56 sig_type=std_logic lab=vss}
C {lab_pin.sym} 1710 -500 0 1 {name=p58 sig_type=std_logic lab=vss}
C {lab_pin.sym} 1710 -340 0 1 {name=p60 sig_type=std_logic lab=vss}
C {lab_pin.sym} 1710 -180 0 1 {name=p62 sig_type=std_logic lab=vss}
C {lab_pin.sym} 1710 -20 0 1 {name=p64 sig_type=std_logic lab=vss}
